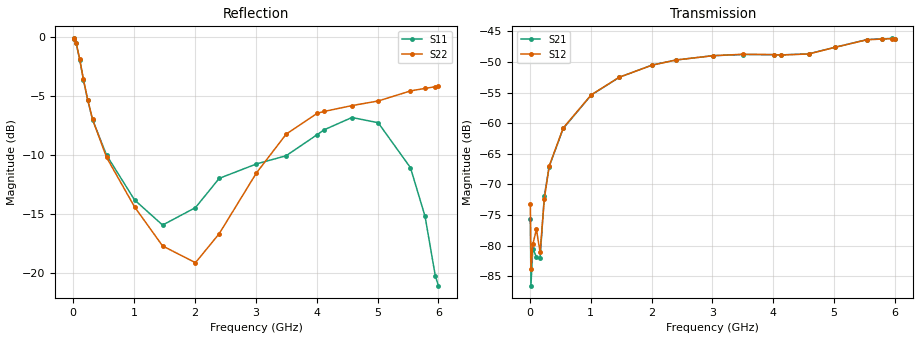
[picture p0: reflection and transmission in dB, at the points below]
!Agilent Technologies,N5230A,MY45001650,A.07.50.48
!Agilent N5230A: A.07.50.48
!Date: Saturday, July 08, 2017 15:55:24
!Correction: S11(Full 2 Port(1,2))
!S21(Full 2 Port(1,2))
!S12(Full 2 Port(1,2))
!S22(Full 2 Port(1,2))
!S2P File: Measurements: S11, S21, S12, S22:
# Hz S  dB  R 50
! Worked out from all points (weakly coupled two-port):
!   600 points, 10 MHz to 6 GHz, reference 50 ohm
!   highest |S21| = -46.17 dB at 5.95 GHz (marker M1); lowest = -86.5 dB at 20 MHz (marker M2)
!   lowest |S11| = -21.1 dB at 6 GHz (marker M3), VSWR 1.19, Z = 59.6 + j1.15 ohm
!   |S11| at or under -10 dB: 548.7 MHz to 3.537 GHz (2.988 GHz wide, 146 % of centre); 5.439 GHz to end of sweep
!   |S22| runs from -19.6 to -0.1 dB; largest |S21 - S12| = 0.00027
!   S11 on the Smith chart (normalised r, x): 10 MHz: 2, -19; 110 MHz: 0.50, -1.81; 320 MHz: 0.52, -0.54; 2.4 GHz: 0.61, +0.09; 4.12 GHz: 1.66, +0.93; 6 GHz: 1.19, +0.02
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1e7  -0.11 -6.0  -75.67 -96.1  -73.13 -9.3  -0.11 -5.5
2e7  -0.16 -11.5  -86.51 -128.3  -83.83 104.0  -0.14 -10.5
5e7  -0.51 -27.6  -80.45 30.2  -79.78 26.4  -0.48 -25.4
1.1e8  -1.94 -55.1  -81.82 15.4  -77.31 50.8  -1.89 -50.6
1.7e8  -3.63 -75.9  -82.05 103.2  -81.09 117.6  -3.59 -69.4
2.4e8  -5.33 -94.5  -71.82 106.5  -72.33 104.4  -5.30 -86.0
3.2e8  -7.01 -112.0  -67.07 94.0  -66.97 94.4  -6.98 -100.4
5.5e8  -10.01 -146.8  -60.87 61.9  -60.78 61.6  -10.20 -128.2
1.01e9  -13.81 178.4  -55.42 15.5  -55.38 15.5  -14.40 -155.2
1.47e9  -15.94 167.5  -52.52 -26.5  -52.51 -26.5  -17.71 -170.0
2.01e9  -14.46 174.7  -50.52 -75.7  -50.54 -75.9  -19.13 -169.9
2.4e9  -11.98 163.8  -49.70 -111.2  -49.70 -111.3  -16.67 -175.1
3.01e9  -10.76 131.2  -48.99 -168.2  -49.00 -168.2  -11.53 168.5
3.5e9  -10.06 89.5  -48.81 145.5  -48.76 145.7  -8.23 154.9
4.01e9  -8.27 42.7  -48.83 99.5  -48.82 99.3  -6.46 139.6
4.12e9  -7.87 35.2  -48.87 90.2  -48.88 90.5  -6.31 136.5
4.58e9  -6.82 10.5  -48.70 55.5  -48.72 55.6  -5.81 119.6
5.01e9  -7.26 -5.8  -47.63 22.5  -47.64 22.6  -5.42 101.6
5.54e9  -11.07 -20.7  -46.37 -26.6  -46.39 -26.4  -4.57 76.8
5.78e9  -15.19 -20.5  -46.25 -48.9  -46.29 -48.8  -4.35 64.0
5.95e9  -20.28 -4.2  -46.17 -64.3  -46.21 -64.2  -4.21 54.8
6e9  -21.08 6.2  -46.21 -68.8  -46.20 -68.4  -4.17 52.0
